VERSION 5.4 ;
NAMESCASESENSITIVE ON ;
BUSBITCHARS "[]" ;
DIVIDERCHAR "/" ;
UNITS
  DATABASE MICRONS 2000 ;
END UNITS
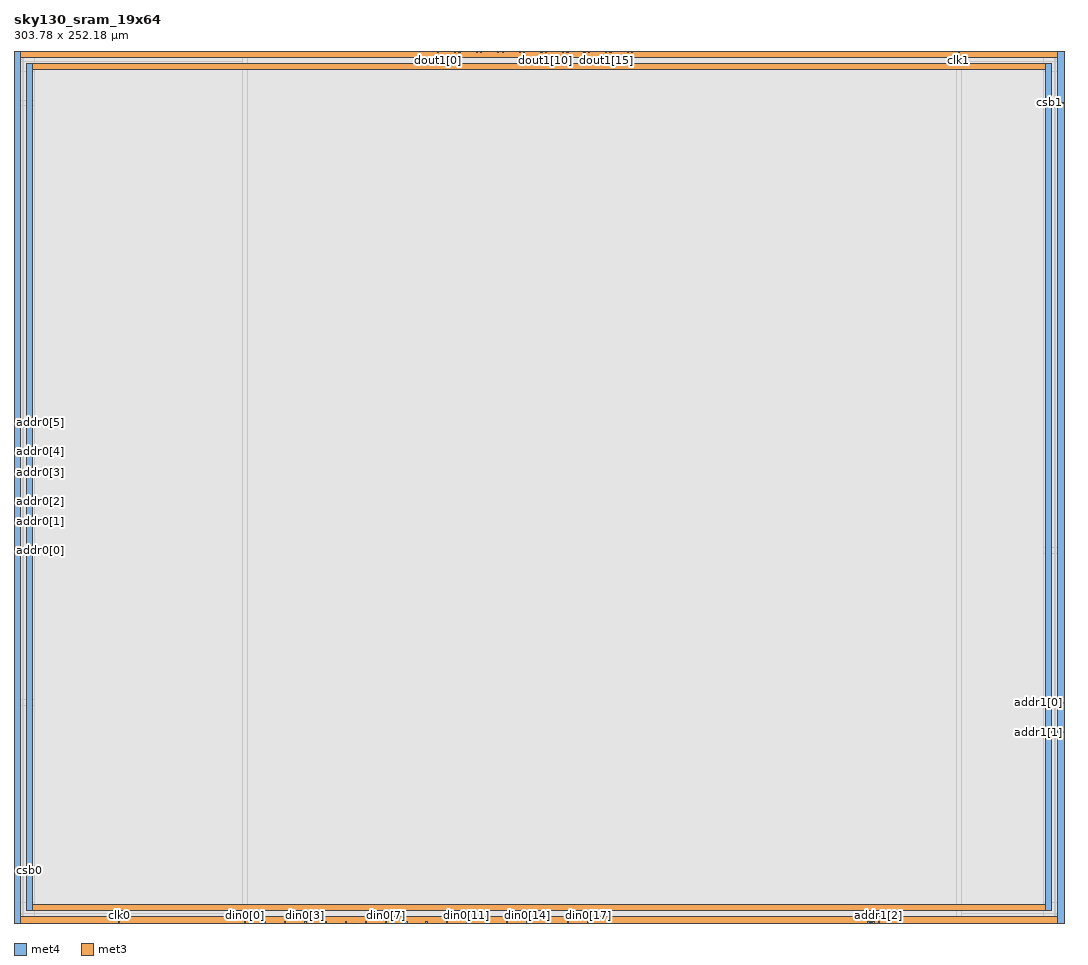
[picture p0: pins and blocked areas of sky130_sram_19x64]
MACRO sky130_sram_19x64
   CLASS BLOCK ;
   SIZE 303.78 BY 252.18 ;
   SYMMETRY X Y R90 ;
   PIN din0[0]
      DIRECTION INPUT ;
      PORT
         LAYER met4 ;
         RECT  66.62 0.0 67.0 0.38 ;
      END
   END din0[0]
   PIN din0[1]
      DIRECTION INPUT ;
      PORT
         LAYER met4 ;
         RECT  72.46 0.0 72.84 0.38 ;
      END
   END din0[1]
   PIN din0[2]
      DIRECTION INPUT ;
      PORT
         LAYER met4 ;
         RECT  78.3 0.0 78.68 0.38 ;
      END
   END din0[2]
   PIN din0[3]
      DIRECTION INPUT ;
      PORT
         LAYER met4 ;
         RECT  84.14 0.0 84.52 0.38 ;
      END
   END din0[3]
   PIN din0[4]
      DIRECTION INPUT ;
      PORT
         LAYER met4 ;
         RECT  89.98 0.0 90.36 0.38 ;
      END
   END din0[4]
   PIN din0[5]
      DIRECTION INPUT ;
      PORT
         LAYER met4 ;
         RECT  95.82 0.0 96.2 0.38 ;
      END
   END din0[5]
   PIN din0[6]
      DIRECTION INPUT ;
      PORT
         LAYER met4 ;
         RECT  101.66 0.0 102.04 0.38 ;
      END
   END din0[6]
   PIN din0[7]
      DIRECTION INPUT ;
      PORT
         LAYER met4 ;
         RECT  107.5 0.0 107.88 0.38 ;
      END
   END din0[7]
   PIN din0[8]
      DIRECTION INPUT ;
      PORT
         LAYER met4 ;
         RECT  113.34 0.0 113.72 0.38 ;
      END
   END din0[8]
   PIN din0[9]
      DIRECTION INPUT ;
      PORT
         LAYER met4 ;
         RECT  119.18 0.0 119.56 0.38 ;
      END
   END din0[9]
   PIN din0[10]
      DIRECTION INPUT ;
      PORT
         LAYER met4 ;
         RECT  125.02 0.0 125.4 0.38 ;
      END
   END din0[10]
   PIN din0[11]
      DIRECTION INPUT ;
      PORT
         LAYER met4 ;
         RECT  130.86 0.0 131.24 0.38 ;
      END
   END din0[11]
   PIN din0[12]
      DIRECTION INPUT ;
      PORT
         LAYER met4 ;
         RECT  136.7 0.0 137.08 0.38 ;
      END
   END din0[12]
   PIN din0[13]
      DIRECTION INPUT ;
      PORT
         LAYER met4 ;
         RECT  142.54 0.0 142.92 0.38 ;
      END
   END din0[13]
   PIN din0[14]
      DIRECTION INPUT ;
      PORT
         LAYER met4 ;
         RECT  148.38 0.0 148.76 0.38 ;
      END
   END din0[14]
   PIN din0[15]
      DIRECTION INPUT ;
      PORT
         LAYER met4 ;
         RECT  154.22 0.0 154.6 0.38 ;
      END
   END din0[15]
   PIN din0[16]
      DIRECTION INPUT ;
      PORT
         LAYER met4 ;
         RECT  160.06 0.0 160.44 0.38 ;
      END
   END din0[16]
   PIN din0[17]
      DIRECTION INPUT ;
      PORT
         LAYER met4 ;
         RECT  165.9 0.0 166.28 0.38 ;
      END
   END din0[17]
   PIN din0[18]
      DIRECTION INPUT ;
      PORT
         LAYER met4 ;
         RECT  171.74 0.0 172.12 0.38 ;
      END
   END din0[18]
   PIN addr0[0]
      DIRECTION INPUT ;
      PORT
         LAYER met3 ;
         RECT  0.0 107.58 0.38 107.96 ;
      END
   END addr0[0]
   PIN addr0[1]
      DIRECTION INPUT ;
      PORT
         LAYER met3 ;
         RECT  0.0 116.08 0.38 116.46 ;
      END
   END addr0[1]
   PIN addr0[2]
      DIRECTION INPUT ;
      PORT
         LAYER met3 ;
         RECT  0.0 121.72 0.38 122.1 ;
      END
   END addr0[2]
   PIN addr0[3]
      DIRECTION INPUT ;
      PORT
         LAYER met3 ;
         RECT  0.0 130.22 0.38 130.6 ;
      END
   END addr0[3]
   PIN addr0[4]
      DIRECTION INPUT ;
      PORT
         LAYER met3 ;
         RECT  0.0 136.275 0.38 136.655 ;
      END
   END addr0[4]
   PIN addr0[5]
      DIRECTION INPUT ;
      PORT
         LAYER met3 ;
         RECT  0.0 144.675 0.38 145.055 ;
      END
   END addr0[5]
   PIN addr1[0]
      DIRECTION INPUT ;
      PORT
         LAYER met3 ;
         RECT  303.4 63.54 303.78 63.92 ;
      END
   END addr1[0]
   PIN addr1[1]
      DIRECTION INPUT ;
      PORT
         LAYER met3 ;
         RECT  303.4 55.04 303.78 55.42 ;
      END
   END addr1[1]
   PIN addr1[2]
      DIRECTION INPUT ;
      PORT
         LAYER met4 ;
         RECT  250.0 0.0 250.38 0.38 ;
      END
   END addr1[2]
   PIN addr1[3]
      DIRECTION INPUT ;
      PORT
         LAYER met4 ;
         RECT  247.025 0.0 247.405 0.38 ;
      END
   END addr1[3]
   PIN addr1[4]
      DIRECTION INPUT ;
      PORT
         LAYER met4 ;
         RECT  247.715 0.0 248.095 0.38 ;
      END
   END addr1[4]
   PIN addr1[5]
      DIRECTION INPUT ;
      PORT
         LAYER met4 ;
         RECT  248.46 0.0 248.84 0.38 ;
      END
   END addr1[5]
   PIN csb0
      DIRECTION INPUT ;
      PORT
         LAYER met3 ;
         RECT  0.0 14.87 0.38 15.25 ;
      END
   END csb0
   PIN csb1
      DIRECTION INPUT ;
      PORT
         LAYER met3 ;
         RECT  303.4 237.075 303.78 237.455 ;
      END
   END csb1
   PIN clk0
      DIRECTION INPUT ;
      PORT
         LAYER met4 ;
         RECT  30.26 0.0 30.64 0.38 ;
      END
   END clk0
   PIN clk1
      DIRECTION INPUT ;
      PORT
         LAYER met4 ;
         RECT  273.14 251.8 273.52 252.18 ;
      END
   END clk1
   PIN dout1[0]
      DIRECTION OUTPUT ;
      PORT
         LAYER met4 ;
         RECT  122.485 251.8 122.865 252.18 ;
      END
   END dout1[0]
   PIN dout1[1]
      DIRECTION OUTPUT ;
      PORT
         LAYER met4 ;
         RECT  127.455 251.8 127.835 252.18 ;
      END
   END dout1[1]
   PIN dout1[2]
      DIRECTION OUTPUT ;
      PORT
         LAYER met4 ;
         RECT  128.725 251.8 129.105 252.18 ;
      END
   END dout1[2]
   PIN dout1[3]
      DIRECTION OUTPUT ;
      PORT
         LAYER met4 ;
         RECT  133.695 251.8 134.075 252.18 ;
      END
   END dout1[3]
   PIN dout1[4]
      DIRECTION OUTPUT ;
      PORT
         LAYER met4 ;
         RECT  134.965 251.8 135.345 252.18 ;
      END
   END dout1[4]
   PIN dout1[5]
      DIRECTION OUTPUT ;
      PORT
         LAYER met4 ;
         RECT  139.935 251.8 140.315 252.18 ;
      END
   END dout1[5]
   PIN dout1[6]
      DIRECTION OUTPUT ;
      PORT
         LAYER met4 ;
         RECT  141.205 251.8 141.585 252.18 ;
      END
   END dout1[6]
   PIN dout1[7]
      DIRECTION OUTPUT ;
      PORT
         LAYER met4 ;
         RECT  146.175 251.8 146.555 252.18 ;
      END
   END dout1[7]
   PIN dout1[8]
      DIRECTION OUTPUT ;
      PORT
         LAYER met4 ;
         RECT  147.445 251.8 147.825 252.18 ;
      END
   END dout1[8]
   PIN dout1[9]
      DIRECTION OUTPUT ;
      PORT
         LAYER met4 ;
         RECT  152.415 251.8 152.795 252.18 ;
      END
   END dout1[9]
   PIN dout1[10]
      DIRECTION OUTPUT ;
      PORT
         LAYER met4 ;
         RECT  153.685 251.8 154.065 252.18 ;
      END
   END dout1[10]
   PIN dout1[11]
      DIRECTION OUTPUT ;
      PORT
         LAYER met4 ;
         RECT  158.655 251.8 159.035 252.18 ;
      END
   END dout1[11]
   PIN dout1[12]
      DIRECTION OUTPUT ;
      PORT
         LAYER met4 ;
         RECT  159.925 251.8 160.305 252.18 ;
      END
   END dout1[12]
   PIN dout1[13]
      DIRECTION OUTPUT ;
      PORT
         LAYER met4 ;
         RECT  164.895 251.8 165.275 252.18 ;
      END
   END dout1[13]
   PIN dout1[14]
      DIRECTION OUTPUT ;
      PORT
         LAYER met4 ;
         RECT  166.165 251.8 166.545 252.18 ;
      END
   END dout1[14]
   PIN dout1[15]
      DIRECTION OUTPUT ;
      PORT
         LAYER met4 ;
         RECT  171.135 251.8 171.515 252.18 ;
      END
   END dout1[15]
   PIN dout1[16]
      DIRECTION OUTPUT ;
      PORT
         LAYER met4 ;
         RECT  172.405 251.8 172.785 252.18 ;
      END
   END dout1[16]
   PIN dout1[17]
      DIRECTION OUTPUT ;
      PORT
         LAYER met4 ;
         RECT  177.375 251.8 177.755 252.18 ;
      END
   END dout1[17]
   PIN dout1[18]
      DIRECTION OUTPUT ;
      PORT
         LAYER met4 ;
         RECT  178.645 251.8 179.025 252.18 ;
      END
   END dout1[18]
   PIN vccd1
      DIRECTION INOUT ;
      USE POWER ; 
      SHAPE ABUTMENT ; 
      PORT
         LAYER met3 ;
         RECT  0.0 0.0 303.78 1.74 ;
         LAYER met4 ;
         RECT  0.0 0.0 1.74 252.18 ;
         LAYER met4 ;
         RECT  302.04 0.0 303.78 252.18 ;
         LAYER met3 ;
         RECT  0.0 250.44 303.78 252.18 ;
      END
   END vccd1
   PIN vssd1
      DIRECTION INOUT ;
      USE GROUND ; 
      SHAPE ABUTMENT ; 
      PORT
         LAYER met3 ;
         RECT  3.48 246.96 300.3 248.7 ;
         LAYER met3 ;
         RECT  3.48 3.48 300.3 5.22 ;
         LAYER met4 ;
         RECT  298.56 3.48 300.3 248.7 ;
         LAYER met4 ;
         RECT  3.48 3.48 5.22 248.7 ;
      END
   END vssd1
   OBS
   LAYER  met1 ;
      RECT  0.62 0.62 303.16 251.56 ;
   LAYER  met2 ;
      RECT  0.62 0.62 303.16 251.56 ;
   LAYER  met3 ;
      RECT  0.98 106.98 303.16 108.56 ;
      RECT  0.62 108.56 0.98 115.48 ;
      RECT  0.62 117.06 0.98 121.12 ;
      RECT  0.62 122.7 0.98 129.62 ;
      RECT  0.62 131.2 0.98 135.675 ;
      RECT  0.62 137.255 0.98 144.075 ;
      RECT  0.98 62.94 302.8 64.52 ;
      RECT  0.98 64.52 302.8 106.98 ;
      RECT  302.8 64.52 303.16 106.98 ;
      RECT  302.8 56.02 303.16 62.94 ;
      RECT  0.62 15.85 0.98 106.98 ;
      RECT  0.98 108.56 302.8 236.475 ;
      RECT  0.98 236.475 302.8 238.055 ;
      RECT  302.8 108.56 303.16 236.475 ;
      RECT  302.8 2.34 303.16 54.44 ;
      RECT  0.62 2.34 0.98 14.27 ;
      RECT  0.62 145.655 0.98 249.84 ;
      RECT  302.8 238.055 303.16 249.84 ;
      RECT  0.98 238.055 2.88 246.36 ;
      RECT  0.98 246.36 2.88 249.3 ;
      RECT  0.98 249.3 2.88 249.84 ;
      RECT  2.88 238.055 300.9 246.36 ;
      RECT  2.88 249.3 300.9 249.84 ;
      RECT  300.9 238.055 302.8 246.36 ;
      RECT  300.9 246.36 302.8 249.3 ;
      RECT  300.9 249.3 302.8 249.84 ;
      RECT  0.98 2.34 2.88 2.88 ;
      RECT  0.98 2.88 2.88 5.82 ;
      RECT  0.98 5.82 2.88 62.94 ;
      RECT  2.88 2.34 300.9 2.88 ;
      RECT  2.88 5.82 300.9 62.94 ;
      RECT  300.9 2.34 302.8 2.88 ;
      RECT  300.9 2.88 302.8 5.82 ;
      RECT  300.9 5.82 302.8 62.94 ;
   LAYER  met4 ;
      RECT  66.02 0.98 67.6 251.56 ;
      RECT  67.6 0.62 71.86 0.98 ;
      RECT  73.44 0.62 77.7 0.98 ;
      RECT  79.28 0.62 83.54 0.98 ;
      RECT  85.12 0.62 89.38 0.98 ;
      RECT  90.96 0.62 95.22 0.98 ;
      RECT  96.8 0.62 101.06 0.98 ;
      RECT  102.64 0.62 106.9 0.98 ;
      RECT  108.48 0.62 112.74 0.98 ;
      RECT  114.32 0.62 118.58 0.98 ;
      RECT  120.16 0.62 124.42 0.98 ;
      RECT  126.0 0.62 130.26 0.98 ;
      RECT  131.84 0.62 136.1 0.98 ;
      RECT  137.68 0.62 141.94 0.98 ;
      RECT  143.52 0.62 147.78 0.98 ;
      RECT  149.36 0.62 153.62 0.98 ;
      RECT  155.2 0.62 159.46 0.98 ;
      RECT  161.04 0.62 165.3 0.98 ;
      RECT  166.88 0.62 171.14 0.98 ;
      RECT  172.72 0.62 246.425 0.98 ;
      RECT  31.24 0.62 66.02 0.98 ;
      RECT  67.6 0.98 272.54 251.2 ;
      RECT  272.54 0.98 274.12 251.2 ;
      RECT  67.6 251.2 121.885 251.56 ;
      RECT  123.465 251.2 126.855 251.56 ;
      RECT  129.705 251.2 133.095 251.56 ;
      RECT  135.945 251.2 139.335 251.56 ;
      RECT  142.185 251.2 145.575 251.56 ;
      RECT  148.425 251.2 151.815 251.56 ;
      RECT  154.665 251.2 158.055 251.56 ;
      RECT  160.905 251.2 164.295 251.56 ;
      RECT  167.145 251.2 170.535 251.56 ;
      RECT  173.385 251.2 176.775 251.56 ;
      RECT  179.625 251.2 272.54 251.56 ;
      RECT  2.34 0.62 29.66 0.98 ;
      RECT  250.98 0.62 301.44 0.98 ;
      RECT  274.12 251.2 301.44 251.56 ;
      RECT  274.12 0.98 297.96 2.88 ;
      RECT  274.12 2.88 297.96 249.3 ;
      RECT  274.12 249.3 297.96 251.2 ;
      RECT  297.96 0.98 300.9 2.88 ;
      RECT  297.96 249.3 300.9 251.2 ;
      RECT  300.9 0.98 301.44 2.88 ;
      RECT  300.9 2.88 301.44 249.3 ;
      RECT  300.9 249.3 301.44 251.2 ;
      RECT  2.34 0.98 2.88 2.88 ;
      RECT  2.34 2.88 2.88 249.3 ;
      RECT  2.34 249.3 2.88 251.56 ;
      RECT  2.88 0.98 5.82 2.88 ;
      RECT  2.88 249.3 5.82 251.56 ;
      RECT  5.82 0.98 66.02 2.88 ;
      RECT  5.82 2.88 66.02 249.3 ;
      RECT  5.82 249.3 66.02 251.56 ;
   END
END    sky130_sram_19x64
END    LIBRARY
